VERSION 5.7 ;
  NOWIREEXTENSIONATPIN ON ;
  DIVIDERCHAR "/" ;
  BUSBITCHARS "[]" ;
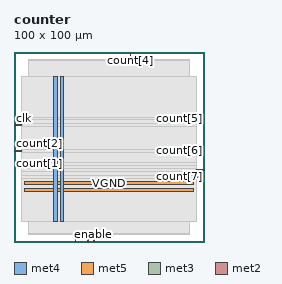
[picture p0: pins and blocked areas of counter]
MACRO counter
  CLASS BLOCK ;
  FOREIGN counter ;
  ORIGIN 0.000 0.000 ;
  SIZE 100.000 BY 100.000 ;
  PIN VGND
    DIRECTION INOUT ;
    USE GROUND ;
    PORT
      LAYER met4 ;
        RECT 24.340 10.640 25.940 87.280 ;
    END
    PORT
      LAYER met5 ;
        RECT 5.280 30.030 94.540 31.630 ;
    END
  END VGND
  PIN VPWR
    DIRECTION INOUT ;
    USE POWER ;
    PORT
      LAYER met4 ;
        RECT 21.040 10.640 22.640 87.280 ;
    END
    PORT
      LAYER met5 ;
        RECT 5.280 26.730 94.540 28.330 ;
    END
  END VPWR
  PIN clk
    DIRECTION INPUT ;
    USE SIGNAL ;
    ANTENNAGATEAREA 0.852000 ;
    PORT
      LAYER met3 ;
        RECT 0.000 64.640 4.000 65.240 ;
    END
  END clk
  PIN count[0]
    DIRECTION OUTPUT ;
    USE SIGNAL ;
    ANTENNADIFFAREA 0.445500 ;
    PORT
      LAYER met2 ;
        RECT 38.730 0.000 39.010 4.000 ;
    END
  END count[0]
  PIN count[1]
    DIRECTION OUTPUT ;
    USE SIGNAL ;
    ANTENNADIFFAREA 0.445500 ;
    PORT
      LAYER met3 ;
        RECT 0.000 40.840 4.000 41.440 ;
    END
  END count[1]
  PIN count[2]
    DIRECTION OUTPUT ;
    USE SIGNAL ;
    ANTENNADIFFAREA 0.445500 ;
    PORT
      LAYER met3 ;
        RECT 0.000 47.640 4.000 48.240 ;
    END
  END count[2]
  PIN count[3]
    DIRECTION OUTPUT ;
    USE SIGNAL ;
    ANTENNADIFFAREA 0.445500 ;
    PORT
      LAYER met3 ;
        RECT 0.000 61.240 4.000 61.840 ;
    END
  END count[3]
  PIN count[4]
    DIRECTION OUTPUT ;
    USE SIGNAL ;
    ANTENNADIFFAREA 0.445500 ;
    PORT
      LAYER met2 ;
        RECT 61.270 96.000 61.550 100.000 ;
    END
  END count[4]
  PIN count[5]
    DIRECTION OUTPUT ;
    USE SIGNAL ;
    ANTENNADIFFAREA 0.445500 ;
    PORT
      LAYER met3 ;
        RECT 96.000 64.640 100.000 65.240 ;
    END
  END count[5]
  PIN count[6]
    DIRECTION OUTPUT ;
    USE SIGNAL ;
    ANTENNADIFFAREA 0.445500 ;
    PORT
      LAYER met3 ;
        RECT 96.000 47.640 100.000 48.240 ;
    END
  END count[6]
  PIN count[7]
    DIRECTION OUTPUT ;
    USE SIGNAL ;
    ANTENNADIFFAREA 0.445500 ;
    PORT
      LAYER met3 ;
        RECT 96.000 34.040 100.000 34.640 ;
    END
  END count[7]
  PIN enable
    DIRECTION INPUT ;
    USE SIGNAL ;
    ANTENNAGATEAREA 0.196500 ;
    PORT
      LAYER met2 ;
        RECT 41.950 0.000 42.230 4.000 ;
    END
  END enable
  PIN overflow
    DIRECTION OUTPUT ;
    USE SIGNAL ;
    ANTENNADIFFAREA 0.445500 ;
    PORT
      LAYER met3 ;
        RECT 96.000 37.440 100.000 38.040 ;
    END
  END overflow
  PIN rst_n
    DIRECTION INPUT ;
    USE SIGNAL ;
    ANTENNAGATEAREA 0.213000 ;
    PORT
      LAYER met2 ;
        RECT 32.290 0.000 32.570 4.000 ;
    END
  END rst_n
  OBS
      LAYER nwell ;
        RECT 5.330 10.795 94.490 87.125 ;
      LAYER li1 ;
        RECT 5.520 10.795 94.300 87.125 ;
      LAYER met1 ;
        RECT 5.520 10.640 94.300 87.280 ;
      LAYER met2 ;
        RECT 7.450 95.720 60.990 96.000 ;
        RECT 61.830 95.720 92.370 96.000 ;
        RECT 7.450 4.280 92.370 95.720 ;
        RECT 7.450 4.000 32.010 4.280 ;
        RECT 32.850 4.000 38.450 4.280 ;
        RECT 39.290 4.000 41.670 4.280 ;
        RECT 42.510 4.000 92.370 4.280 ;
      LAYER met3 ;
        RECT 4.000 65.640 96.000 87.205 ;
        RECT 4.400 64.240 95.600 65.640 ;
        RECT 4.000 62.240 96.000 64.240 ;
        RECT 4.400 60.840 96.000 62.240 ;
        RECT 4.000 48.640 96.000 60.840 ;
        RECT 4.400 47.240 95.600 48.640 ;
        RECT 4.000 41.840 96.000 47.240 ;
        RECT 4.400 40.440 96.000 41.840 ;
        RECT 4.000 38.440 96.000 40.440 ;
        RECT 4.000 37.040 95.600 38.440 ;
        RECT 4.000 35.040 96.000 37.040 ;
        RECT 4.000 33.640 95.600 35.040 ;
        RECT 4.000 10.715 96.000 33.640 ;
  END
END counter
END LIBRARY

